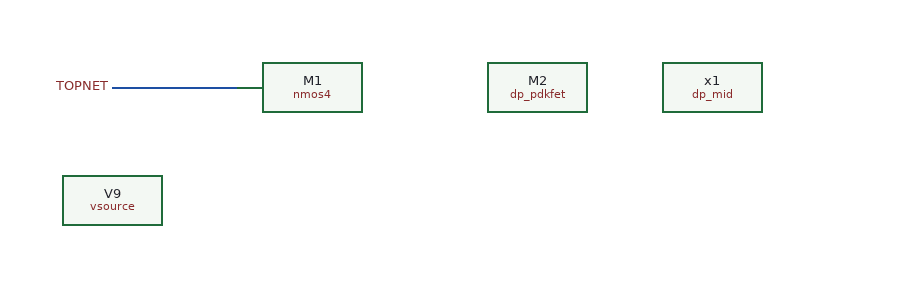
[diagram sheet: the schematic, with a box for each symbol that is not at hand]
v {xschem version=3.4.4 file_version=1.2}
G {}
V {}
S {}
E {}
N 0 0 100 0 {}
C {devices/lab_pin.sym} 0 0 0 0 {name=l1 lab=TOPNET}
C {devices/nmos4.sym} 200 0 0 0 {name=M1 model=nmos w=5u l=0.18u m=1}
C {dp_pdkfet.sym} 340 0 0 0 {name=M2 model=dpfet_01v8 W=1 L=0.15 spiceprefix=X}
C {devices/vsource.sym} 0 90 0 0 {name=V9 value=1}
C {dp_mid.sym} 480 0 0 0 {name=x1}
